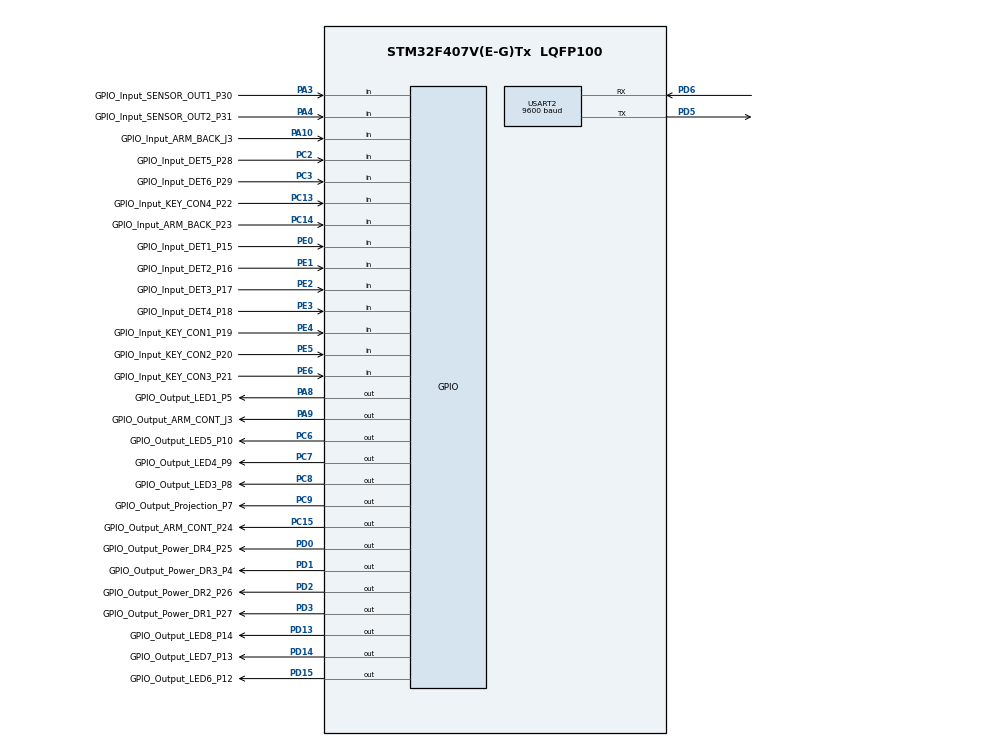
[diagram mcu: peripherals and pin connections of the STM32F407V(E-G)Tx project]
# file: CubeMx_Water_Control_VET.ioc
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FREERTOS.Tasks01=defaultTask,0,128,StartDefaultTask,Default,NULL,Dynamic,NULL,NULL;RecvProcesTask,0,128,StartTaskRecvProcess,Default,NULL,Dynamic,NULL,NULL;WaterControlTas,0,128,StartTaskWaterControl,Default,NULL,Dynamic,NULL,NULL
Mcu.Family=STM32F4
Mcu.Name=STM32F407V(E-G)Tx
Mcu.Package=LQFP100
NVIC.PriorityGroup=NVIC_PRIORITYGROUP_4
NVIC.TIM2_IRQn=true\:5\:0\:false\:false\:true\:true\:true\:true
NVIC.TIM3_IRQn=true\:5\:0\:false\:false\:true\:true\:true\:true
NVIC.USART2_IRQn=true\:5\:0\:false\:false\:true\:true\:true\:true
PA10.GPIO_Label=GPIO_Input_ARM_BACK_J3
PA10.Signal=GPIO_Input
PA3.GPIO_Label=GPIO_Input_SENSOR_OUT1_P30
PA3.Signal=GPIO_Input
PA4.GPIO_Label=GPIO_Input_SENSOR_OUT2_P31
PA4.Signal=GPIO_Input
PA8.GPIO_Label=GPIO_Output_LED1_P5
PA8.PinState=GPIO_PIN_RESET
PA8.Signal=GPIO_Output
PA9.GPIO_Label=GPIO_Output_ARM_CONT_J3
PA9.Signal=GPIO_Output
PC13-ANTI_TAMP.GPIO_Label=GPIO_Input_KEY_CON4_P22
PC13-ANTI_TAMP.Signal=GPIO_Input
PC14-OSC32_IN.GPIO_Label=GPIO_Input_ARM_BACK_P23
PC14-OSC32_IN.Signal=GPIO_Input
PC15-OSC32_OUT.GPIO_Label=GPIO_Output_ARM_CONT_P24
PC15-OSC32_OUT.Signal=GPIO_Output
PC2.GPIO_Label=GPIO_Input_DET5_P28
PC2.Signal=GPIO_Input
PC3.GPIO_Label=GPIO_Input_DET6_P29
PC3.Signal=GPIO_Input
PC6.GPIO_Label=GPIO_Output_LED5_P10
PC6.PinState=GPIO_PIN_RESET
PC6.Signal=GPIO_Output
PC7.GPIO_Label=GPIO_Output_LED4_P9
PC7.PinState=GPIO_PIN_RESET
PC7.Signal=GPIO_Output
PC8.GPIO_Label=GPIO_Output_LED3_P8
PC8.Signal=GPIO_Output
PC9.GPIO_Label=GPIO_Output_Projection_P7
PC9.Signal=GPIO_Output
PD0.GPIO_Label=GPIO_Output_Power_DR4_P25
PD0.Signal=GPIO_Output
PD1.GPIO_Label=GPIO_Output_Power_DR3_P4
PD1.Signal=GPIO_Output
PD13.GPIO_Label=GPIO_Output_LED8_P14
PD13.PinState=GPIO_PIN_RESET
PD13.Signal=GPIO_Output
PD14.GPIO_Label=GPIO_Output_LED7_P13
PD14.PinState=GPIO_PIN_RESET
PD14.Signal=GPIO_Output
PD15.GPIO_Label=GPIO_Output_LED6_P12
PD15.PinState=GPIO_PIN_RESET
PD15.Signal=GPIO_Output
PD2.GPIO_Label=GPIO_Output_Power_DR2_P26
PD2.Signal=GPIO_Output
PD3.GPIO_Label=GPIO_Output_Power_DR1_P27
PD3.Signal=GPIO_Output
PD5.Mode=Asynchronous
PD5.Signal=USART2_TX
PD6.Mode=Asynchronous
PD6.Signal=USART2_RX
PE0.GPIO_Label=GPIO_Input_DET1_P15
PE0.Signal=GPIO_Input
PE1.GPIO_Label=GPIO_Input_DET2_P16
PE1.Signal=GPIO_Input
PE2.GPIO_Label=GPIO_Input_DET3_P17
PE2.Signal=GPIO_Input
PE3.GPIO_Label=GPIO_Input_DET4_P18
PE3.Signal=GPIO_Input
PE4.GPIO_Label=GPIO_Input_KEY_CON1_P19
PE4.Signal=GPIO_Input
PE5.GPIO_Label=GPIO_Input_KEY_CON2_P20
PE5.Signal=GPIO_Input
PE6.GPIO_Label=GPIO_Input_KEY_CON3_P21
PE6.Signal=GPIO_Input
PH0-OSC_IN.Mode=HSE-External-Oscillator
PH0-OSC_IN.Signal=RCC_OSC_IN
PH1-OSC_OUT.Mode=HSE-External-Oscillator
PH1-OSC_OUT.Signal=RCC_OSC_OUT
ProjectManager.HeapSize=0x200
ProjectManager.StackSize=0x400
ProjectManager.TargetToolchain=MDK-ARM V5.27
RCC.48MHZClocksFreq_Value=84000000
RCC.AHBFreq_Value=168000000
RCC.APB1CLKDivider=RCC_HCLK_DIV4
RCC.APB1Freq_Value=42000000
RCC.APB1TimFreq_Value=84000000
RCC.APB2CLKDivider=RCC_HCLK_DIV2
RCC.APB2Freq_Value=84000000
RCC.APB2TimFreq_Value=168000000
RCC.CortexFreq_Value=168000000
RCC.HCLKFreq_Value=168000000
RCC.HSE_VALUE=25000000
RCC.HSI_VALUE=16000000
RCC.LSE_VALUE=32768
RCC.PLLM=8
RCC.PLLN=168
RCC.SYSCLKFreq_VALUE=168000000
RCC.SYSCLKSource=RCC_SYSCLKSOURCE_PLLCLK
RCC.VCOOutputFreq_Value=336000000
TIM2.Channel-Output\ Compare1\ No\ Output=TIM_CHANNEL_1
TIM2.Period=35
TIM2.Prescaler=9600-1
TIM2.Pulse-Output\ Compare1\ No\ Output=50
TIM3.Period=99
TIM3.Prescaler=16800-1
USART2.BaudRate=9600
USART2.VirtualMode=VM_ASYNC
VP_FREERTOS_VS_CMSIS_V1.Mode=CMSIS_V1
VP_TIM2_VS_ClockSourceINT.Mode=Internal
VP_TIM2_VS_no_output1.Mode=Output Compare1 No Output
VP_TIM3_VS_ClockSourceINT.Mode=Internal
board=custom

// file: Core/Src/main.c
/* USER CODE BEGIN Header */
/**
  ******************************************************************************
  * @file           : main.c
  * @brief          : Main program body
  ******************************************************************************
  * @attention
  *
  * <h2><center>&copy; Copyright (c) 2019 STMicroelectronics.
  * All rights reserved.</center></h2>
  *
  * This software component is licensed by ST under Ultimate Liberty license
  * SLA0044, the "License"; You may not use this file except in compliance with
  * the License. You may obtain a copy of the License at:
  *                             www.st.com/SLA0044
  *
  ******************************************************************************
  */
/* USER CODE END Header */

#include "main.h"
#include "cmsis_os.h"
#include "tim.h"
#include "usart.h"
#include "gpio.h"

/* USER CODE BEGIN PV */

extern osSemaphoreId myBinarySem01Handle;

/* USER CODE END PV */

void SystemClock_Config(void);
void MX_FREERTOS_Init(void);

int main(void)
{

  /* MCU Configuration--------------------------------------------------------*/

  /* Reset of all peripherals, Initializes the Flash interface and the Systick. */
  HAL_Init();

  /* Configure the system clock */
  SystemClock_Config();

  /* Initialize all configured peripherals */
  MX_GPIO_Init();
  MX_TIM3_Init();
  MX_USART2_UART_Init();
  MX_TIM2_Init();

  /* Call init function for freertos objects (in freertos.c) */
  MX_FREERTOS_Init();

  /* Start scheduler */
  osKernelStart();

  /* We should never get here as control is now taken by the scheduler */

  /* Infinite loop */
  while (1)
  {

  }
}

void SystemClock_Config(void)
{
  RCC_OscInitTypeDef RCC_OscInitStruct = {0};
  RCC_ClkInitTypeDef RCC_ClkInitStruct = {0};

  /** Configure the main internal regulator output voltage
  */
  __HAL_RCC_PWR_CLK_ENABLE();
  __HAL_PWR_VOLTAGESCALING_CONFIG(PWR_REGULATOR_VOLTAGE_SCALE1);
  /** Initializes the CPU, AHB and APB busses clocks
  */
  RCC_OscInitStruct.OscillatorType = RCC_OSCILLATORTYPE_HSI;
  RCC_OscInitStruct.HSIState = RCC_HSI_ON;
  RCC_OscInitStruct.HSICalibrationValue = RCC_HSICALIBRATION_DEFAULT;
  RCC_OscInitStruct.PLL.PLLState = RCC_PLL_ON;
  RCC_OscInitStruct.PLL.PLLSource = RCC_PLLSOURCE_HSI;
  RCC_OscInitStruct.PLL.PLLM = 8;
  RCC_OscInitStruct.PLL.PLLN = 96;
  RCC_OscInitStruct.PLL.PLLP = RCC_PLLP_DIV2;
  RCC_OscInitStruct.PLL.PLLQ = 4;
  if (HAL_RCC_OscConfig(&RCC_OscInitStruct) != HAL_OK)
  {
    Error_Handler();
  }
  /** Initializes the CPU, AHB and APB busses clocks
  */
  RCC_ClkInitStruct.ClockType = RCC_CLOCKTYPE_HCLK|RCC_CLOCKTYPE_SYSCLK
                              |RCC_CLOCKTYPE_PCLK1|RCC_CLOCKTYPE_PCLK2;
  RCC_ClkInitStruct.SYSCLKSource = RCC_SYSCLKSOURCE_PLLCLK;
  RCC_ClkInitStruct.AHBCLKDivider = RCC_SYSCLK_DIV1;
  RCC_ClkInitStruct.APB1CLKDivider = RCC_HCLK_DIV4;
  RCC_ClkInitStruct.APB2CLKDivider = RCC_HCLK_DIV2;

  if (HAL_RCC_ClockConfig(&RCC_ClkInitStruct, FLASH_LATENCY_3) != HAL_OK)
  {
    Error_Handler();
  }
}

/* USER CODE BEGIN 4 */
void HAL_UART_RxCpltCallback(UART_HandleTypeDef *huart)
{
	if(huart->Instance==USART2)
	{
		__HAL_TIM_SET_COUNTER(&htim3,0);
		if(0==RxCounter)
		{
			__HAL_TIM_CLEAR_FLAG(&htim3,TIM_FLAG_UPDATE);
			HAL_TIM_Base_Start_IT(&htim3);
		}
		RxBuffer[RxCounter]=RxTemp[0];
		RxCounter++;
		HAL_UART_Receive_IT(&huart2,(uint8_t *)RxTemp,REC_LENGTH);
	}
}
/* USER CODE END 4 */

void HAL_TIM_PeriodElapsedCallback(TIM_HandleTypeDef *htim)
{
  /* USER CODE BEGIN Callback 0 */
	UBaseType_t uxSavedInterruptStatus;

	if	(htim->Instance==TIM2)
	{
		uxSavedInterruptStatus=taskENTER_CRITICAL_FROM_ISR();
		TimCount++;
		if(TimCount>0xfe)
		TimCount=0;
		//RunLed_TOGGLE;
		taskEXIT_CRITICAL_FROM_ISR( uxSavedInterruptStatus );

	}
  /* USER CODE END Callback 0 */
  if (htim->Instance == TIM1) {
    HAL_IncTick();
  }
  /* USER CODE BEGIN Callback 1 */
	if(htim->Instance==TIM3)
	{
//		HAL_GPIO_TogglePin(GPIOB,GPIO_PIN_7);
		HAL_GPIO_TogglePin(GPIOF,GPIO_PIN_9);
		RxFlag=1;
		HAL_TIM_Base_Stop_IT(&htim3);
		osSemaphoreRelease(myBinarySem01Handle);
	}
  /* USER CODE END Callback 1 */
}

void Error_Handler(void)
{
}

/************************ (C) COPYRIGHT STMicroelectronics *****END OF FILE****/

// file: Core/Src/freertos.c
/* USER CODE BEGIN Header */
/**
  ******************************************************************************
  * File Name          : freertos.c
  * Description        : Code for freertos applications
  ******************************************************************************
  * @attention
  *
  * <h2><center>&copy; Copyright (c) 2019 STMicroelectronics.
  * All rights reserved.</center></h2>
  *
  * This software component is licensed by ST under Ultimate Liberty license
  * SLA0044, the "License"; You may not use this file except in compliance with
  * the License. You may obtain a copy of the License at:
  *                             www.st.com/SLA0044
  *
  ******************************************************************************
  */
/* USER CODE END Header */

#include "FreeRTOS.h"
#include "task.h"
#include "main.h"
#include "cmsis_os.h"

/* USER CODE BEGIN Includes */
#include "usart.h"
#include "Global_include.h"
/* USER CODE END Includes */

osThreadId defaultTaskHandle;
osThreadId myTask02Handle;
osSemaphoreId myBinarySem01Handle;

/* USER CODE BEGIN FunctionPrototypes */
extern void Uart2RecvProcess(void);
/* USER CODE END FunctionPrototypes */

void StartDefaultTask(void const * argument);
void StartTask02(void const * argument);

void MX_FREERTOS_Init(void); /* (MISRA C 2004 rule 8.1) */

/* GetIdleTaskMemory prototype (linked to static allocation support) */
void vApplicationGetIdleTaskMemory( StaticTask_t **ppxIdleTaskTCBBuffer, StackType_t **ppxIdleTaskStackBuffer, uint32_t *pulIdleTaskStackSize );

/* USER CODE BEGIN GET_IDLE_TASK_MEMORY */
static StaticTask_t xIdleTaskTCBBuffer;
static StackType_t xIdleStack[configMINIMAL_STACK_SIZE];

void vApplicationGetIdleTaskMemory( StaticTask_t **ppxIdleTaskTCBBuffer, StackType_t **ppxIdleTaskStackBuffer, uint32_t *pulIdleTaskStackSize )
{
  *ppxIdleTaskTCBBuffer = &xIdleTaskTCBBuffer;
  *ppxIdleTaskStackBuffer = &xIdleStack[0];
  *pulIdleTaskStackSize = configMINIMAL_STACK_SIZE;
  /* place for user code */
}
/* USER CODE END GET_IDLE_TASK_MEMORY */

void MX_FREERTOS_Init(void) {

  /* Create the semaphores(s) */
  /* definition and creation of myBinarySem01 */
  osSemaphoreDef(myBinarySem01);
  myBinarySem01Handle = osSemaphoreCreate(osSemaphore(myBinarySem01), 1);

  /* Create the thread(s) */
  /* definition and creation of defaultTask */
  osThreadDef(defaultTask, StartDefaultTask, osPriorityNormal, 0, 128);
  defaultTaskHandle = osThreadCreate(osThread(defaultTask), NULL);

  /* definition and creation of myTask02 */
  osThreadDef(myTask02, StartTask02, osPriorityNormal, 0, 128);
  myTask02Handle = osThreadCreate(osThread(myTask02), NULL);

}

void StartDefaultTask(void const * argument)
{
  /* USER CODE BEGIN StartDefaultTask */
  HAL_UART_Receive_IT(&huart2,(uint8_t *)RxTemp,REC_LENGTH);
	/* Infinite loop */
  for(;;)
  {
    HAL_GPIO_TogglePin(GPIOB,GPIO_PIN_14);
		osDelay(200);
  }
  /* USER CODE END StartDefaultTask */
}

void StartTask02(void const * argument)
{
  /* USER CODE BEGIN StartTask02 */
  /* Infinite loop */
  for(;;)
  {
    osSemaphoreWait(myBinarySem01Handle,100);
		Uart2RecvProcess();
//		uart_test();
//		printf("a\r\n");

  }
  /* USER CODE END StartTask02 */
}

/* USER CODE BEGIN Application */

//void uart_test(void)
//{
//  if(RxFlag==1)
//	{
////		HAL_UART_Transmit(&huart2,RxBuffer,RxCounter,0xffff);
//		uint8_t UartTxPkg[32];
//		uint8_t UartTxCnt = 0;
//		uint8_t frame_head,frame_cmd;
//		int diff_norel;
//		int diff_rel;
//		uint8_t i;
//		uint8_t temp_light;
//		uint8_t temp_projection;
//		uint8_t temp_valve;
//
//		UartTxCnt = RxCounter;//��ȡ֡��
//		for(i = 0; i < UartTxCnt; i++)
//		{
//			UartTxPkg[i] = RxBuffer[i];
//		}
//		frame_head = UartTxPkg[0];
//		frame_cmd = UartTxPkg[1];

////		printf("frame_head:%X\r\n", UartTxPkg[0]);
////		printf("frame_cmd:%X\r\n", UartTxPkg[1]);
////		printf("third:%X\r\n", UartTxPkg[2]);
////		printf("fourth:%X\r\n", UartTxPkg[3]);
////		printf("fifth:%X\r\n", UartTxPkg[5]);
////		printf("sixth:%X\r\n", UartTxPkg[6]);
////		printf("head long:%d\r\n",UartTxCnt);
////		printf("judge head\r\n");
//		if(frame_head == FRAME_START)/* ֡��ʼ */
//		{
////			printf("enter the head\r\n");
//			if(Crc8_Calc(UartTxPkg, UartTxCnt) == 0)	/* CRC8У�� ��ȷ*/
//			{
////				printf("crc is true\r\n");
//				switch(frame_cmd)
//				{
//					case CMD_CONN:
//						UartTxPkg[UartTxCnt-1]= Crc8_Calc(UartTxPkg, UartTxCnt-1);//У��
//					  UartTxPkg[2]=0X00;
//					  Uart_BspWrite(&huart2,UartTxPkg ,UartTxCnt);
//						break;
//
//					case CMD_QUERY:
//						UartTxPkg[2]=0X08;
//						UartTxPkg[3]=0X00;
//					  UartTxPkg[4]=0X00;
//						UartTxPkg[5]=0Xff;
//						UartTxPkg[6]=0X80;
//						UartTxPkg[7]=0X63;
//					  UartTxPkg[8]=0X00;
//						UartTxPkg[9]=0X63;
//						UartTxPkg[10]=0X00;
//					  UartTxPkg[UartTxCnt-1]= Crc8_Calc(UartTxPkg,UartTxCnt-1);//У��
//					  Uart_BspWrite(&huart2,UartTxPkg,UartTxCnt);
//						break;
//
//					case CMD_ARM_CONTROL_RELEASE:
//
//						UartTxPkg[2]=0X02;
//						UartTxPkg[3]=0X80;
//						diff_rel=UartTxPkg[4]-UartTxPkg[4];
//
//						if(0<=diff_rel&&diff_rel<3)
//						{
//							UartTxPkg[5]=0X00;
//						}else{
//							UartTxPkg[5]=0X01;
//						}
//					  UartTxPkg[UartTxCnt]=Crc8_Calc(UartTxPkg, UartTxCnt+1);
//					  HAL_UART_Transmit(&huart2,UartTxPkg,UartTxCnt+1,0xffff);
//						osDelay(100);
//						UartTxPkg[4]=0x07;
//					  if(UartTxPkg[4]<=0x0A)
//						{
//							UartTxPkg[5]=0X00;
//						}else{
//							UartTxPkg[5]=0X01;
//						}
//						UartTxPkg[UartTxCnt]=Crc8_Calc(UartTxPkg, UartTxCnt+1);
//						HAL_UART_Transmit(&huart2,UartTxPkg,UartTxCnt+1,0xffff);
//						break;
//
//					case CMD_ARM_CONTROL_NORELEASE:
//						UartTxPkg[2]=0X02;
//						UartTxPkg[3]=0X80;
//						diff_norel=UartTxPkg[4]-UartTxPkg[4];
//						if(0<=diff_norel&&diff_norel<3)
//						{
//							UartTxPkg[5]=0X00;
//						}else{
//							UartTxPkg[5]=0X01;
//						}
//					  UartTxPkg[UartTxCnt]=Crc8_Calc(UartTxPkg, UartTxCnt+1);
//					  HAL_UART_Transmit(&huart2,UartTxPkg,UartTxCnt+1,0xffff);
//
//						break;
//
//					case CMD_LIGHT_CONTROL:
//						UartTxPkg[2]=0X01;
//						UartTxPkg[3]=0X84;
//					  temp_light=0X84;

//						if(temp_light==UartTxPkg[3])
//						{
//							UartTxPkg[4]=0X00;
//						}else{
//							UartTxPkg[4]=0X01;
//						}
//					  UartTxPkg[UartTxCnt]=Crc8_Calc(UartTxPkg, UartTxCnt+1);
//					  HAL_UART_Transmit(&huart2,UartTxPkg,UartTxCnt+1,0xffff);
//						break;
//
//					case CMD_VALVE_SWITCH_CONTROL:
//						UartTxPkg[2]=0X01;
//						UartTxPkg[3]=0X40;
//					  temp_valve=0X40;

//						if(temp_valve==UartTxPkg[3])
//						{
//							UartTxPkg[4]=0X00;
//						}else{
//							UartTxPkg[4]=0X01;
//						}
//					  UartTxPkg[UartTxCnt]=Crc8_Calc(UartTxPkg, UartTxCnt+1);
//					  HAL_UART_Transmit(&huart2,UartTxPkg,UartTxCnt+1,0xffff);
//						break;
//
//					case CMD_PROJECTION_SWITCH_CONTROL:
//						UartTxPkg[2]=0X01;
//						UartTxPkg[3]=0X01;
//					  temp_projection=0X01;

//						if(temp_projection==UartTxPkg[3])
//						{
//							UartTxPkg[4]=0X00;
//						}else{
//							UartTxPkg[4]=0X01;
//						}
//					  UartTxPkg[UartTxCnt]=Crc8_Calc(UartTxPkg, UartTxCnt+1);
//					  HAL_UART_Transmit(&huart2,UartTxPkg,UartTxCnt+1,0xffff);
//						break;
//
//					default:
//						break;
//				}

//			}
//			else
//			{
////				printf("crc is error\r\n");
//				uint8_t UartCrcError[1]={0XFF};
//				Uart_BspWrite(&huart2,UartCrcError,1);
//			}
//		}
//		else
//		{
////			printf("head is error��\r\n");
//				uint8_t UartCrcError[1]={0XEE};
//				Uart_BspWrite(&huart2,UartCrcError,1);
//		}
//
//		RxFlag=0;
//		RxCounter=0;
//		memset(RxBuffer,0,MAX_REC_LENGTH);
//	}
//		osDelay(1);
//
//}

/* USER CODE END Application */

/************************ (C) COPYRIGHT STMicroelectronics *****END OF FILE****/
